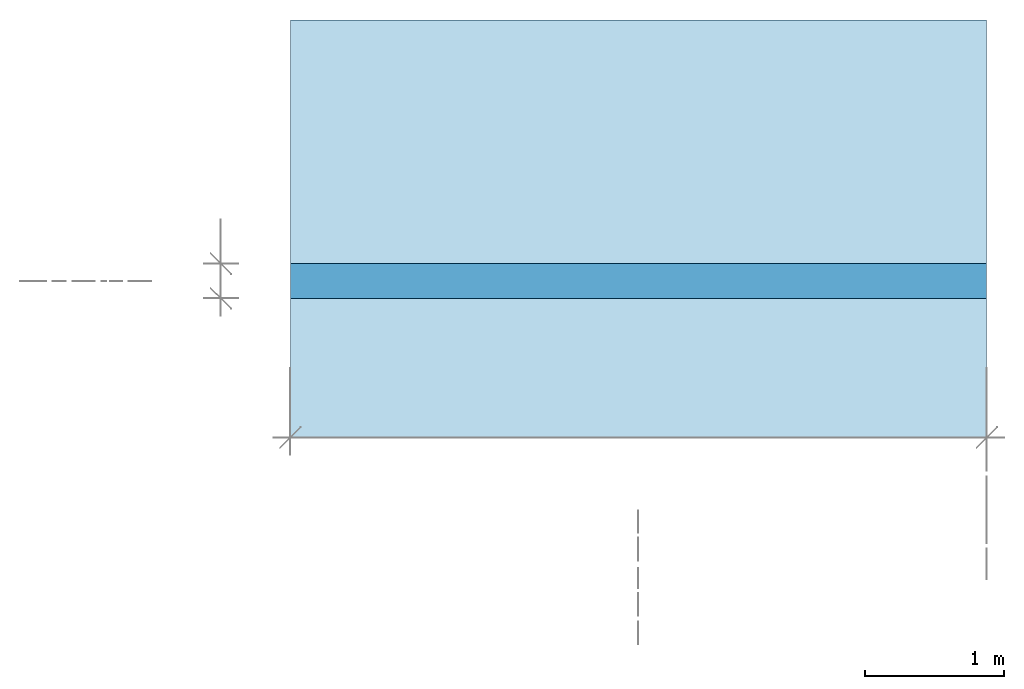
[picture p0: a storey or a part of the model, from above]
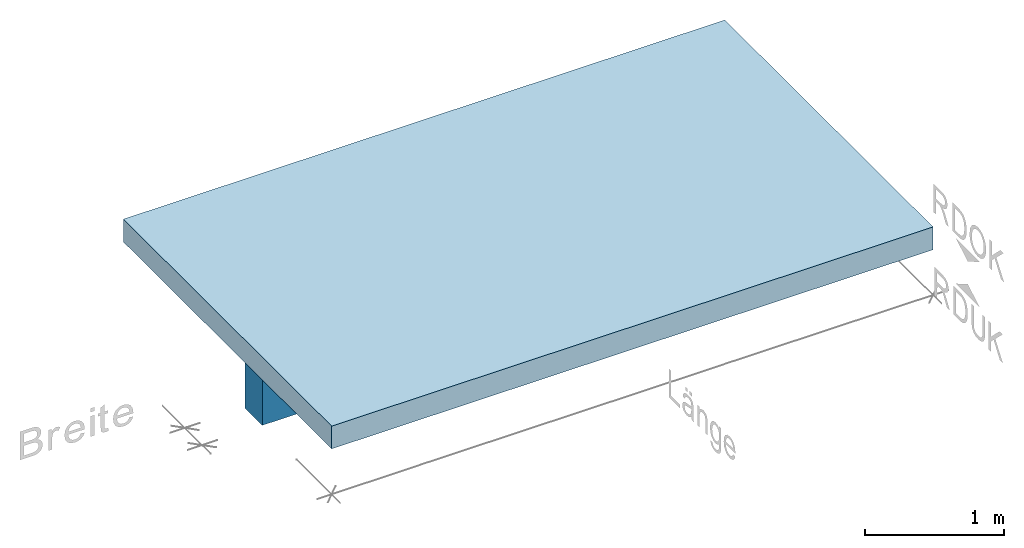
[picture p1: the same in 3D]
Properties of the parts of a building model (IFC4)

# File
Description: no view
File name: ÖBV_OEBV_Richtlinie_Träger.ifc
Time: 2024-03-13T09:39:59
Author: Oesterreichische Bautechnik Vereinigung
Organization: OEBV
Written by: ODA SDAI 24.5
Authorization: OEBV

# IfcSite, Liegenschaft
RefLatitude: 48, 8, 10, 320000; RefLongitude: 11, 41, 19, 320000

# IfcBuildingStorey (2)
In: Gebäude
Elevation: 0 m
Name
Geschoss 01
Geschoss 02

# IfcBeam (2)
Description: Innenwand; Material: C25/30
Name | In | Allright_Bauteil_ID
WA_01 | Geschoss 01 | 0012Unz0000000004
WA_01 | Geschoss 02 | 0062Unz0000000014

# IfcBuildingElementProxy (8)
Name | In | Allright_Bauteil_ID
macro | Geschoss 01 | 0012Mak0000000047
macro | Geschoss 01 | 0012Mak0000000058
macro | Geschoss 01 | 0012Mak0000000082
macro | Geschoss 01 | 0012Mak0000000094
RDOK | Geschoss 01 | 0012Mak0000000110
RDUK | Geschoss 01 | 0012Mak0000000121
macro | Geschoss 02 | 0062Mak0000000005
macro | Geschoss 02 | 0062Mak0000000010

# IfcElementAssembly (8)
Name | In | Allright_Bauteil_ID
SpatialDim_Group | Geschoss 01 | 0012Elg0000000048
SpatialDim_Group | Geschoss 01 | 0012Elg0000000059
SpatialDim_Group | Geschoss 01 | 0012Elg0000000083
SpatialDim_Group | Geschoss 01 | 0012Elg0000000095
SpatialDim_Group | Geschoss 01 | 0012Elg0000000111
SpatialDim_Group | Geschoss 01 | 0012Elg0000000122
SpatialDim_Group | Geschoss 02 | 0062Elg0000000006
SpatialDim_Group | Geschoss 02 | 0062Elg0000000011

# IfcSlab
In: Geschoss 01
PredefinedType: FLOOR
AllplanAttributes - Allright_Bauteil_ID: 0012De 0000000998
